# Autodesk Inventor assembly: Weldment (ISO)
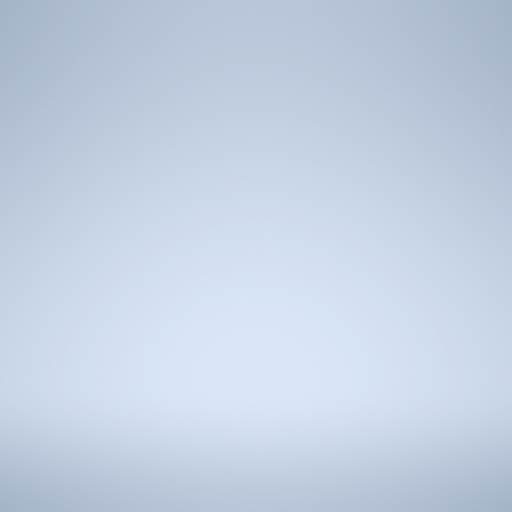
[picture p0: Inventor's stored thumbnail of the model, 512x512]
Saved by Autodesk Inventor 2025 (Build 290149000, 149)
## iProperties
Created: 2024-02
Part Number: Weldment (ISO)
Document SubType Name: Weldment
Weld Material: Welded Aluminum-6061
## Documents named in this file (1)
- C:\Users\enu\Desktop\1\Weldment (ISO).iam
